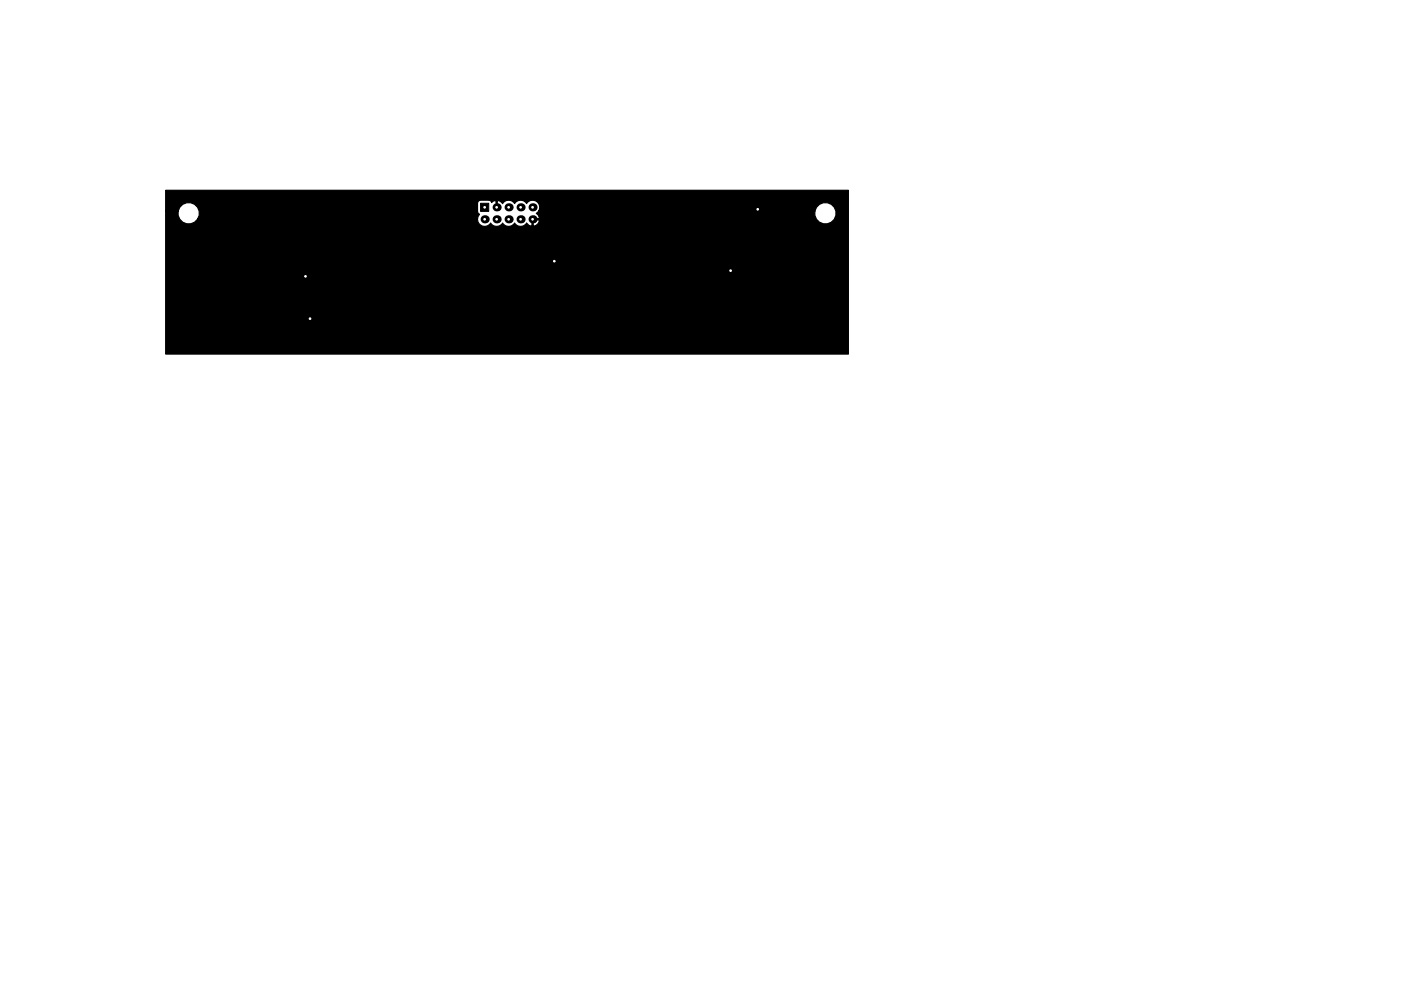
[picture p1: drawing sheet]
<svg xmlns="http://www.w3.org/2000/svg" width="297mm" height="210mm" viewBox="0 0 297 210" stroke-linecap="round" stroke-linejoin="round" font-family="sans-serif">
<g fill="#000">
<circle cx="102.8" cy="46.5" r=".86"/>
<circle cx="105.3" cy="44" r=".86"/>
<circle cx="105.3" cy="46.5" r=".86"/>
<circle cx="107.8" cy="44" r=".86"/>
<circle cx="107.8" cy="46.5" r=".86"/>
<circle cx="110.4" cy="46.5" r=".86"/>
<circle cx="110.4" cy="44" r=".86"/>
<circle cx="112.9" cy="46.5" r=".86"/>
<circle cx="112.9" cy="44" r=".86"/>
</g>
<g fill="#000" stroke="#000" stroke-width=".21">
<path d="M101.9 43.1h1.7v1.8h-1.7z"/>
<circle cx="64.8" cy="58.6" r=".6"/>
<circle cx="117.5" cy="55.4" r=".6"/>
<circle cx="154.9" cy="57.4" r=".6"/>
<circle cx="160.7" cy="44.4" r=".6"/>
<circle cx="65.7" cy="67.6" r=".6"/>
</g>
<path d="M64.8 58.6l.9 1v8M160.7 44.4l-5.8 5.8v7.2h-2l-2-2h-33.4" fill="none" stroke="#000" stroke-width=".35"/>
<path d="M35.1 40.4h144.8v34.7h-144.8v-30.3h2.7a2.28 2.28 0 0 0 1.3 2.5 2.28 2.28 0 0 0 2.8-.8h59.3a1.52 1.52 0 0 0 1.1 1.5 1.52 1.52 0 0 0 1.7-.7 1.49 1.49 0 0 0 2.6 0 1.49 1.49 0 0 0 2.5 0 1.49 1.49 0 0 0 2.6 0l.4 .5 .5 .2 .2-.1v-1.2h.2v1.2a1.09 1.09 0 0 0 1.4-1l-.1-.2h-1.5v-.3h1.5l.1-.2-.3-.6-.4-.3 .5-.5h58.6a2.28 2.28 0 0 0 2.6 2.7 2.28 2.28 0 0 0 1.5-3.5 2.28 2.28 0 0 0-3.8 0l-.3 .8h-58.6a1.5 1.5 0 0 0-.5-2.1 1.5 1.5 0 0 0-2.1 .5 1.49 1.49 0 0 0-2.5 0 1.49 1.49 0 0 0-2.5 0l-.5-.5-.4-.2-.3 .2v1.4h-.2v-1.4l-.3-.2-.7 .5-.3-.5h-2a.65 .65 0 0 0-.7 .6v1.8l.2 .4 .3 .2-.4 .4-.1 .6h-59.3a2.28 2.28 0 0 0-1-3.4 2.28 2.28 0 0 0-3.1 1.7h-2.7z" fill="#000" stroke="#000" stroke-width=".25"/>
<g fill="#fff" stroke="#fff" stroke-width=".21">
<circle cx="117.5" cy="55.4" r=".17"/>
<circle cx="154.9" cy="57.4" r=".17"/>
<circle cx="160.7" cy="44.4" r=".17"/>
<circle cx="64.8" cy="58.6" r=".17"/>
<circle cx="65.7" cy="67.6" r=".17"/>
<circle cx="112.9" cy="46.5" r=".17"/>
<circle cx="112.9" cy="44" r=".17"/>
<circle cx="110.4" cy="46.5" r=".17"/>
<circle cx="110.4" cy="44" r=".17"/>
<circle cx="107.8" cy="46.5" r=".17"/>
<circle cx="107.8" cy="44" r=".17"/>
<circle cx="105.3" cy="46.5" r=".17"/>
<circle cx="105.3" cy="44" r=".17"/>
<circle cx="102.8" cy="46.5" r=".17"/>
<circle cx="102.8" cy="44" r=".17"/>
<circle cx="175" cy="45.2" r=".18"/>
<circle cx="40" cy="45.2" r=".18"/>
</g>
</svg>
